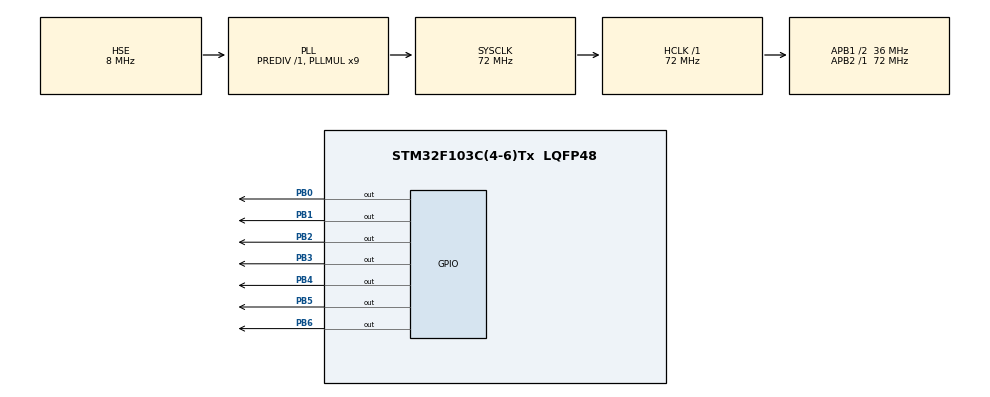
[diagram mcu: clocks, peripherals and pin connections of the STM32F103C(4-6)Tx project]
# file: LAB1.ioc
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Mcu.Family=STM32F1
Mcu.Name=STM32F103C(4-6)Tx
Mcu.Package=LQFP48
NVIC.PriorityGroup=NVIC_PRIORITYGROUP_4
PB0.Signal=GPIO_Output
PB1.Signal=GPIO_Output
PB2.Signal=GPIO_Output
PB3.Signal=GPIO_Output
PB4.Signal=GPIO_Output
PB5.Signal=GPIO_Output
PB6.Signal=GPIO_Output
PD0-OSC_IN.Mode=HSE-External-Oscillator
PD0-OSC_IN.Signal=RCC_OSC_IN
PD1-OSC_OUT.Mode=HSE-External-Oscillator
PD1-OSC_OUT.Signal=RCC_OSC_OUT
ProjectManager.HeapSize=0x200
ProjectManager.StackSize=0x400
ProjectManager.TargetToolchain=STM32CubeIDE
RCC.AHBFreq_Value=72000000
RCC.APB1CLKDivider=RCC_HCLK_DIV2
RCC.APB1Freq_Value=36000000
RCC.APB1TimFreq_Value=72000000
RCC.APB2Freq_Value=72000000
RCC.APB2TimFreq_Value=72000000
RCC.HCLKFreq_Value=72000000
RCC.PLLMUL=RCC_PLL_MUL9
RCC.PLLSourceVirtual=RCC_PLLSOURCE_HSE
RCC.SYSCLKFreq_VALUE=72000000
RCC.SYSCLKSource=RCC_SYSCLKSOURCE_PLLCLK
RCC.USBFreq_Value=72000000
board=custom

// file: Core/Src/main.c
/* USER CODE BEGIN Header */
/**
  ******************************************************************************
  * @file           : main.c
  * @brief          : Main program body
  ******************************************************************************
  * @attention
  *
  * Copyright (c) 2026 STMicroelectronics.
  * All rights reserved.
  *
  * This software is licensed under terms that can be found in the LICENSE file
  * in the root directory of this software component.
  * If no LICENSE file comes with this software, it is provided AS-IS.
  *
  ******************************************************************************
  */
/* USER CODE END Header */
#include "main.h"

void SystemClock_Config(void);
static void MX_GPIO_Init(void);

/* USER CODE BEGIN 0 */

void clearNumberOnClock( int number )
{
	if ( number == 0 )
	{
		HAL_GPIO_WritePin(GPIOA, GPIO_PIN_4, GPIO_PIN_SET);
	}
	else if ( number == 1 )
	{
		HAL_GPIO_WritePin(GPIOA, GPIO_PIN_5, GPIO_PIN_SET);
	}
	else if ( number == 2 )
	{
		HAL_GPIO_WritePin(GPIOA, GPIO_PIN_6, GPIO_PIN_SET);
	}
	else if ( number == 3 )
	{
		HAL_GPIO_WritePin(GPIOA, GPIO_PIN_7, GPIO_PIN_SET);
	}
	else if ( number == 4 )
	{
		HAL_GPIO_WritePin(GPIOA, GPIO_PIN_8, GPIO_PIN_SET);
	}
	else if ( number == 5 )
	{
		HAL_GPIO_WritePin(GPIOA, GPIO_PIN_9, GPIO_PIN_SET);
	}
	else if ( number == 6 )
	{
		HAL_GPIO_WritePin(GPIOA, GPIO_PIN_10, GPIO_PIN_SET);
	}
	else if ( number == 7 )
	{
		HAL_GPIO_WritePin(GPIOA, GPIO_PIN_11, GPIO_PIN_SET);
	}
	else if ( number == 8 )
	{
		HAL_GPIO_WritePin(GPIOA, GPIO_PIN_12, GPIO_PIN_SET);
	}
	else if ( number == 9 )
	{
		HAL_GPIO_WritePin(GPIOA, GPIO_PIN_13, GPIO_PIN_SET);
	}
	else if ( number == 10 )
	{
		HAL_GPIO_WritePin(GPIOA, GPIO_PIN_14, GPIO_PIN_SET);
	}
	else if ( number == 11 )
	{
		HAL_GPIO_WritePin(GPIOA, GPIO_PIN_15, GPIO_PIN_SET);
	}
}
/* USER CODE END 0 */

int main(void)
{

  /* MCU Configuration--------------------------------------------------------*/

  /* Reset of all peripherals, Initializes the Flash interface and the Systick. */
  HAL_Init();

  /* Configure the system clock */
  SystemClock_Config();

  /* Initialize all configured peripherals */
  MX_GPIO_Init();

  /* Infinite loop */
  while (1)
  {

  }
}

void SystemClock_Config(void)
{
  RCC_OscInitTypeDef RCC_OscInitStruct = {0};
  RCC_ClkInitTypeDef RCC_ClkInitStruct = {0};

  /** Initializes the RCC Oscillators according to the specified parameters
  * in the RCC_OscInitTypeDef structure.
  */
  RCC_OscInitStruct.OscillatorType = RCC_OSCILLATORTYPE_HSE;
  RCC_OscInitStruct.HSEState = RCC_HSE_ON;
  RCC_OscInitStruct.HSEPredivValue = RCC_HSE_PREDIV_DIV1;
  RCC_OscInitStruct.HSIState = RCC_HSI_ON;
  RCC_OscInitStruct.PLL.PLLState = RCC_PLL_ON;
  RCC_OscInitStruct.PLL.PLLSource = RCC_PLLSOURCE_HSE;
  RCC_OscInitStruct.PLL.PLLMUL = RCC_PLL_MUL9;
  if (HAL_RCC_OscConfig(&RCC_OscInitStruct) != HAL_OK)
  {
    Error_Handler();
  }

  /** Initializes the CPU, AHB and APB buses clocks
  */
  RCC_ClkInitStruct.ClockType = RCC_CLOCKTYPE_HCLK|RCC_CLOCKTYPE_SYSCLK
                              |RCC_CLOCKTYPE_PCLK1|RCC_CLOCKTYPE_PCLK2;
  RCC_ClkInitStruct.SYSCLKSource = RCC_SYSCLKSOURCE_PLLCLK;
  RCC_ClkInitStruct.AHBCLKDivider = RCC_SYSCLK_DIV1;
  RCC_ClkInitStruct.APB1CLKDivider = RCC_HCLK_DIV2;
  RCC_ClkInitStruct.APB2CLKDivider = RCC_HCLK_DIV1;

  if (HAL_RCC_ClockConfig(&RCC_ClkInitStruct, FLASH_LATENCY_2) != HAL_OK)
  {
    Error_Handler();
  }
}

static void MX_GPIO_Init(void)
{
  GPIO_InitTypeDef GPIO_InitStruct = {0};

  /* GPIO Ports Clock Enable */
  __HAL_RCC_GPIOD_CLK_ENABLE();
  __HAL_RCC_GPIOA_CLK_ENABLE();

  /*Configure GPIO pin Output Level */
  HAL_GPIO_WritePin(GPIOA, GPIO_PIN_4|GPIO_PIN_5|GPIO_PIN_6|GPIO_PIN_7
                          |GPIO_PIN_8|GPIO_PIN_9|GPIO_PIN_10|GPIO_PIN_11
                          |GPIO_PIN_12|GPIO_PIN_13|GPIO_PIN_14|GPIO_PIN_15, GPIO_PIN_RESET);

  /*Configure GPIO pins : PA4 PA5 PA6 PA7
                           PA8 PA9 PA10 PA11
                           PA12 PA13 PA14 PA15 */
  GPIO_InitStruct.Pin = GPIO_PIN_4|GPIO_PIN_5|GPIO_PIN_6|GPIO_PIN_7
                          |GPIO_PIN_8|GPIO_PIN_9|GPIO_PIN_10|GPIO_PIN_11
                          |GPIO_PIN_12|GPIO_PIN_13|GPIO_PIN_14|GPIO_PIN_15;
  GPIO_InitStruct.Mode = GPIO_MODE_OUTPUT_PP;
  GPIO_InitStruct.Pull = GPIO_NOPULL;
  GPIO_InitStruct.Speed = GPIO_SPEED_FREQ_LOW;
  HAL_GPIO_Init(GPIOA, &GPIO_InitStruct);

}

void Error_Handler(void)
{
  __disable_irq();
  while (1)
  {
  }
}
